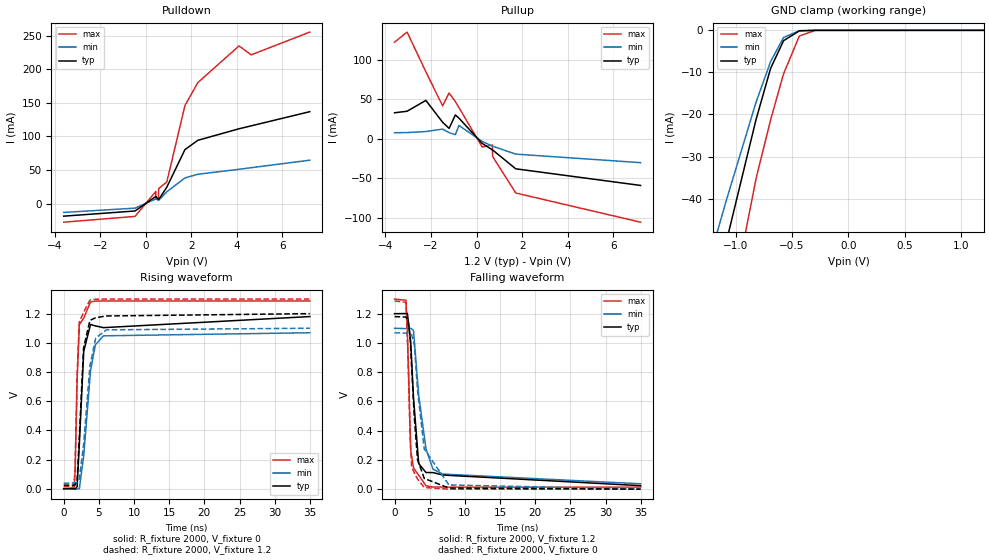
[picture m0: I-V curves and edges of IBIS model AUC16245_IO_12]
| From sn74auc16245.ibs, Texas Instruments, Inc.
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[Model]   AUC16245_IO_12
Model_type  3-state
Enable   Active-Low
Vref =   0
Rref =   2000
Cref =   15p
Vmeas =   0.6
| variable   typ   min   max
C_comp   7pF   NA   NA
| C_pullup   9.14pF   1.34pF   17.64pF
| C_pulldown   14.27pF   7.00pF   23.75pF
| C_tri-state   10.35pF   6.85pF   17.72pF
[Temperature Range]   40   100   -40
| Ambient temperature   25   85   -40
[Voltage range]   1.2   1.1   1.3
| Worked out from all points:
|   slope of the pulldown table from 0 to 0.18 V, typ, clamps not added: 42.1 ohm
|   slope of the pullup table from 0 to 0.18 V, typ, clamps not added: 39 ohm
|   GND clamp passes 1 mA (typ) near -0.52 V on its own axis
|   rising waveform, R_fixture 2000, V_fixture 0: 20-80 % time 685ps typ, 1.1ns min, 404ps max; typ from 0 V to 1.18 V
|   falling waveform, R_fixture 2000, V_fixture 1.2: 20-80 % time 876ps typ, 1.53ns min, 447ps max; typ from 1.2 V to 0.024 V
|   rising waveform, R_fixture 2000, V_fixture 1.2: 20-80 % time 681ps typ, 1.09ns min, 398ps max; typ from 0.024 V to 1.2 V
|   falling waveform, R_fixture 2000, V_fixture 0: 20-80 % time 867ps typ, 1.47ns min, 444ps max; typ from 1.18 V to 0 V
[GND Clamp]
| AUC16245_IO_12
|   Voltage   I(typ)   I(min)   I(max)
-3.6V     -349.5mA   -293.4mA   -425.3mA
-1.44V    -91.84mA   -74.48mA   -122mA
-1.315V   -77.17mA   -62.38mA   -104.2mA
-1.275V   -72.5mA    -58.55mA   -98.57mA
-1.12V    -54.55mA   -43.89mA   -76.58mA
-1.085V   -50.54mA   -40.63mA   -71.64mA
-820mV    -21.3mA    -17.17mA   -35.39mA
-690mV    -9.056mA   -7.439mA   -21.28mA
-575mV    -2.462mA   -1.712mA   -10.33mA
-435mV    -129.5uA   -73.07uA   -1.353mA
-295mV    -2.121uA   -2.64uA    -15.16uA
1.2V      468.4pA    9.297nA    413pA
[Pulldown]
| AUC16245_IO_12
|   Voltage   I(typ)   I(min)   I(max)
-3.6V     -18.86mA   -13.33mA   -27.86mA
-470mV    -11.13mA   -6.909mA   -19.23mA
440mV     10.48mA    6.706mA    17.92mA
445mV     10.59mA    6.769mA    6.318mA
560mV     5.857mA    4.698mA    8.209mA
570mV     5.97mA     4.786mA    22.41mA
925mV     24.38mA    17.54mA    32.09mA
1.72V     80.37mA    38.11mA    146mA
2.285V    94.25mA    43.62mA    180.3mA
4.095V    111.5mA    51.07mA    235.1mA
4.625V    115.8mA    53.41mA    221.7mA
7.2V      137mA      64.62mA    255.7mA
[Pullup]
| AUC16245_IO_12
|   Voltage   I(typ)   I(min)   I(max)
-3.6V     32.81mA    7.559mA    122.1mA
-3.05V    34.76mA    7.793mA    134.9mA
-2.225V   48.49mA    9.074mA    84.66mA
-1.49V    20.8mA     12.2mA     41.58mA
-1.205V   13.08mA    7.707mA    57.86mA
-930mV    30.05mA    5.088mA    46.93mA
-775mV    26.1mA     16.83mA    39.5mA
245mV     -5.916mA   -3.381mA   -10.43mA
690mV     -14.05mA   -9.319mA   -7.997mA
705mV     -14.25mA   -9.473mA   -22.45mA
1.72V     -38.07mA   -19.48mA   -68.67mA
7.2V      -59.11mA   -30.28mA   -105.6mA
[Ramp]
| AUC16245_IO_12
| variable   typ   min   max
dV/dt_r   0.71/7.01E-10   0.64/1.13E-09   0.78/4.20E-10
dV/dt_f   0.71/9.08E-10   0.64/1.55E-09   0.77/4.55E-10
R_load = 2000
[Rising Waveform]
| AUC16245_IO_12
R_fixture =   2000
C_fixture =   0
L_fixture =   0
V_fixture =   0
V_fixture_min = 0
V_fixture_max = 0
|   Time   V(typ)   V(min)   V(max)
0s        8.816nV    37.24nV    1.034nV
1.475ns   -1.306mV   307.9uV    6.484mV
1.625ns   -2.643mV   -871.5uV   119.4mV
1.91ns    14.16mV    -3.36mV    752.1mV
2.225ns   306.4mV    457.4uV    1.125V
2.85ns    942.5mV    227mV      1.17V
3.815ns   1.126V     809.5mV    1.28V
4.495ns   1.116V     985.5mV    1.286V
5.645ns   1.104V     1.048V     1.287V
34.99ns   1.18V      1.069V     1.287V
[Falling Waveform]
| AUC16245_IO_12
R_fixture =   2000
C_fixture =   0
L_fixture =   0
V_fixture =   1.2
V_fixture_min = 1.1
V_fixture_max = 1.3
|   Time   V(typ)   V(min)   V(max)
0s        1.2V       1.1V       1.3V
1.62ns    1.201V     1.098V     1.292V
1.825ns   1.202V     1.099V     1.082V
2.3ns     1.006V     1.1V       267.5mV
2.695ns   625.7mV    1.085V     144.9mV
3.435ns   174.6mV    642.2mV    95.5mV
4.475ns   113.9mV    275.2mV    23.55mV
5.47ns    113.4mV    136.4mV    14.72mV
6.875ns   96.6mV     103.3mV    14.07mV
34.99ns   24.03mV    36.68mV    13.88mV
[Rising Waveform]
| AUC16245_IO_12
R_fixture =   2000
C_fixture =   0
L_fixture =   0
V_fixture =   1.2
V_fixture_min = 1.1
V_fixture_max = 1.3
|   Time   V(typ)   V(min)   V(max)
0s        23.98mV    36.61mV    13.86mV
1.455ns   24.45mV    39.17mV    16.77mV
1.62ns    24.38mV    40.29mV    140.7mV
1.91ns    61.17mV    45.54mV    784.3mV
2.215ns   349.6mV    68.07mV    1.141V
2.815ns   962mV      294.7mV    1.208V
3.725ns   1.154V     841.6mV    1.293V
4.545ns   1.172V     1.032V     1.299V
6.06ns    1.184V     1.089V     1.3V
34.99ns   1.2V       1.1V       1.3V
[Falling Waveform]
| AUC16245_IO_12
R_fixture =   2000
C_fixture =   0
L_fixture =   0
V_fixture =   0
V_fixture_min = 0
V_fixture_max = 0
|   Time   V(typ)   V(min)   V(max)
0s        1.18V      1.069V     1.287V
1.615ns   1.177V     1.067V     1.278V
1.92ns    1.157V     1.065V     899.3mV
2.215ns   1.04V      1.06V      353.7mV
2.43ns    833.8mV    1.056V     151.4mV
2.82ns    482.6mV    986.9mV    111.2mV
3.265ns   203mV      678.5mV    69.35mV
4.225ns   73.55mV    274.9mV    11.17mV
7.725ns   7.845mV    28.99mV    150.5uV
34.99ns   52.69uV    55.37uV    18.55uV
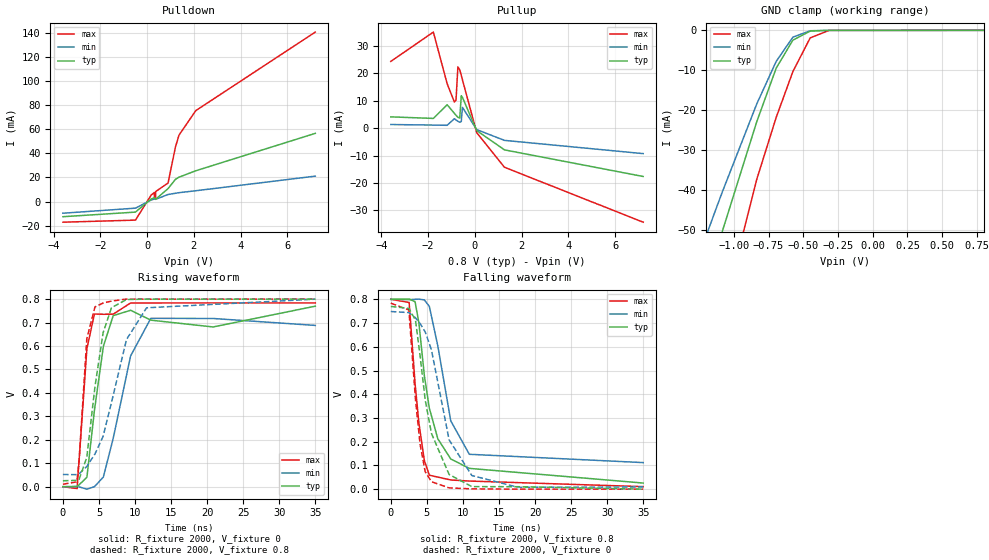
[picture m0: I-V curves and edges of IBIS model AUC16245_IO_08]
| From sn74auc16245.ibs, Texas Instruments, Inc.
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[Model]   AUC16245_IO_08
Model_type  3-state
Enable   Active-Low
Vref =   0
Rref =   2000
Cref =   15p
Vmeas =   0.4
| variable   typ   min   max
C_comp   7pF   NA   NA
| C_pullup   13.21pF   5.05pF   24.95pF
| C_pulldown   16.87pF   7.30pF   33.21pF
| C_tri-state   11.92pF   7.24pF   20.78pF
[Temperature Range]   40   100   -40
| Ambient temperature   25   85   -40
[Voltage range]   0.8   0.8   0.8
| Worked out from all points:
|   slope of the pulldown table from 0 to 0.12 V, typ, clamps not added: 77.5 ohm
|   slope of the pullup table from 0 to 0.12 V, typ, clamps not added: 92.7 ohm
|   GND clamp passes 1 mA (typ) near -0.52 V on its own axis
|   rising waveform, R_fixture 2000, V_fixture 0: 20-80 % time 1.94ns typ, 2.75ns min, 1.04ns max; typ from 0 V to 0.77 V
|   falling waveform, R_fixture 2000, V_fixture 0.8: 20-80 % time 2.97ns typ, 2.48ns min, 1.49ns max; typ from 0.8 V to 0.026 V
|   rising waveform, R_fixture 2000, V_fixture 0.8: 20-80 % time 1.95ns typ, 3.71ns min, 990ps max; typ from 0.025 V to 0.8 V
|   falling waveform, R_fixture 2000, V_fixture 0: 20-80 % time 2.54ns typ, 3.17ns min, 1.37ns max; typ from 0.77 V to 0 V
[GND Clamp]
| AUC16245_IO_08
|   Voltage   I(typ)   I(min)   I(max)
-3.6V     -349.5mA   -293.4mA   -425.3mA
-1.47V    -95.38mA   -77.4mA    -126.3mA
-1.42V    -89.49mA   -72.53mA   -119.2mA
-1.285V   -73.66mA   -59.5mA    -99.99mA
-1.12V    -54.55mA   -43.89mA   -76.58mA
-1.08V    -49.97mA   -40.17mA   -70.93mA
-835mV    -22.86mA   -18.41mA   -37.29mA
-695mV    -9.456mA   -7.767mA   -21.78mA
-575mV    -2.462mA   -1.712mA   -10.33mA
-450mV    -191.3uA   -103.9uA   -1.878mA
-315mV    -3.912uA   -4.474uA   -32.85uA
800mV     338.4pA    610.4pA    260.4pA
[Pulldown]
| AUC16245_IO_08
|   Voltage   I(typ)   I(min)   I(max)
-3.6V     -12.63mA   -9.733mA   -17.19mA
-495mV    -8.803mA   -5.522mA   -15.47mA
175mV     2.059mA    1.185mA    5.31mA
310mV     3.174mA    2.053mA    7.502mA
315mV     3.217mA    2.087mA    2.47mA
365mV     1.856mA    1.796mA    2.807mA
370mV     1.894mA    1.829mA    8.27mA
900mV     10.72mA    5.829mA    15.4mA
1.215V    18.4mA     6.852mA    45.18mA
1.365V    20.2mA     7.318mA    55.07mA
2.085V    25.54mA    8.939mA    75.52mA
7.2V      56.65mA    21.1mA     140.8mA
[Pullup]
| AUC16245_IO_08
|   Voltage   I(typ)   I(min)   I(max)
-3.6V     4.13mA     1.333mA    24.37mA
-1.78V    3.562mA    1.136mA    35.07mA
-1.19V    8.552mA    1.048mA    16.26mA
-880mV    5.425mA    3.46mA     9.531mA
-810mV    4.708mA    3.016mA    10.3mA
-730mV    3.982mA    2.544mA    22.37mA
-650mV    3.702mA    2.149mA    21.3mA
-585mV    11.85mA    2.409mA    19.32mA
-535mV    11.24mA    7.606mA    17.64mA
75mV      -881.4uA   -518.8uA   -1.613mA
1.265V    -7.92mA    -4.455mA   -14.27mA
7.2V      -17.63mA   -9.285mA   -34.31mA
[Ramp]
| AUC16245_IO_08
| variable   typ   min   max
dV/dt_r   0.47/1.97E-09   0.46/3.30E-09   0.48/1.06E-09
dV/dt_f   0.47/3.01E-09   0.42/2.61E-09   0.47/1.49E-09
R_load = 2000
[Rising Waveform]
| AUC16245_IO_08
R_fixture =   2000
C_fixture =   0
L_fixture =   0
V_fixture =   0
V_fixture_min = 0
V_fixture_max = 0
|   Time   V(typ)   V(min)   V(max)
0s        10.82nV    60.83nV    758.4pV
1.97ns    -147.2uV   1.785mV    -7.918mV
3.33ns    40.3mV     -10.43mV   589.8mV
4.375ns   326.6mV    229uV      736.5mV
5.61ns    598.5mV    41.28mV    735.3mV
6.975ns   729.5mV    206.3mV    735.8mV
9.385ns   752.4mV    557.5mV    783.5mV
12.19ns   710.3mV    718.1mV    783.5mV
20.82ns   681.2mV    717.4mV    783.7mV
34.99ns   769.9mV    687.8mV    783.7mV
[Falling Waveform]
| AUC16245_IO_08
R_fixture =   2000
C_fixture =   0
L_fixture =   0
V_fixture =   0.8
V_fixture_min = 0.8
V_fixture_max = 0.8
|   Time   V(typ)   V(min)   V(max)
0s        800mV      800mV      800mV
2.54ns    801.1mV    798.8mV    786.7mV
3.365ns   790mV      800mV      444mV
3.895ns   700.4mV    800.8mV    277.8mV
4.65ns    478.7mV    797.5mV    120.4mV
5.34ns    341.2mV    770.2mV    58.86mV
6.52ns    212mV      603mV      50.78mV
8.31ns    127.3mV    287.8mV    38.72mV
10.88ns   87.67mV    147mV      34.26mV
34.99ns   25.8mV     112mV      10.64mV
[Rising Waveform]
| AUC16245_IO_08
R_fixture =   2000
C_fixture =   0
L_fixture =   0
V_fixture =   0.8
V_fixture_min = 0.8
V_fixture_max = 0.8
|   Time   V(typ)   V(min)   V(max)
0s        25.46mV    51.93mV    10.6mV
1.94ns    27.14mV    51.55mV    20.88mV
2.25ns    31.59mV    55.45mV    112.5mV
3.315ns   125.5mV    86.23mV    631.4mV
4.445ns   426.7mV    139.6mV    766.5mV
5.575ns   656.5mV    215.1mV    783.3mV
6.735ns   763.4mV    359.1mV    791.5mV
8.815ns   798.1mV    627.5mV    800.2mV
11.6ns    799.9mV    763mV      799.7mV
34.99ns   799.9mV    799.7mV    800mV
[Falling Waveform]
| AUC16245_IO_08
R_fixture =   2000
C_fixture =   0
L_fixture =   0
V_fixture =   0
V_fixture_min = 0
V_fixture_max = 0
|   Time   V(typ)   V(min)   V(max)
0s        770mV      748.6mV    783.8mV
2.5ns     761.9mV    744.1mV    755.1mV
3.42ns    712.7mV    722mV      377.8mV
4.055ns   562.3mV    698.5mV    189.2mV
4.77ns    375.6mV    662.4mV    73.09mV
5.635ns   234.9mV    587mV      31.38mV
8.08ns    62.18mV    208mV      5.386mV
11.23ns   10.76mV    57.61mV    1.29mV
17.68ns   10.36mV    7.602mV    99.58uV
34.99ns   137.3uV    9.446mV    37.55uV
